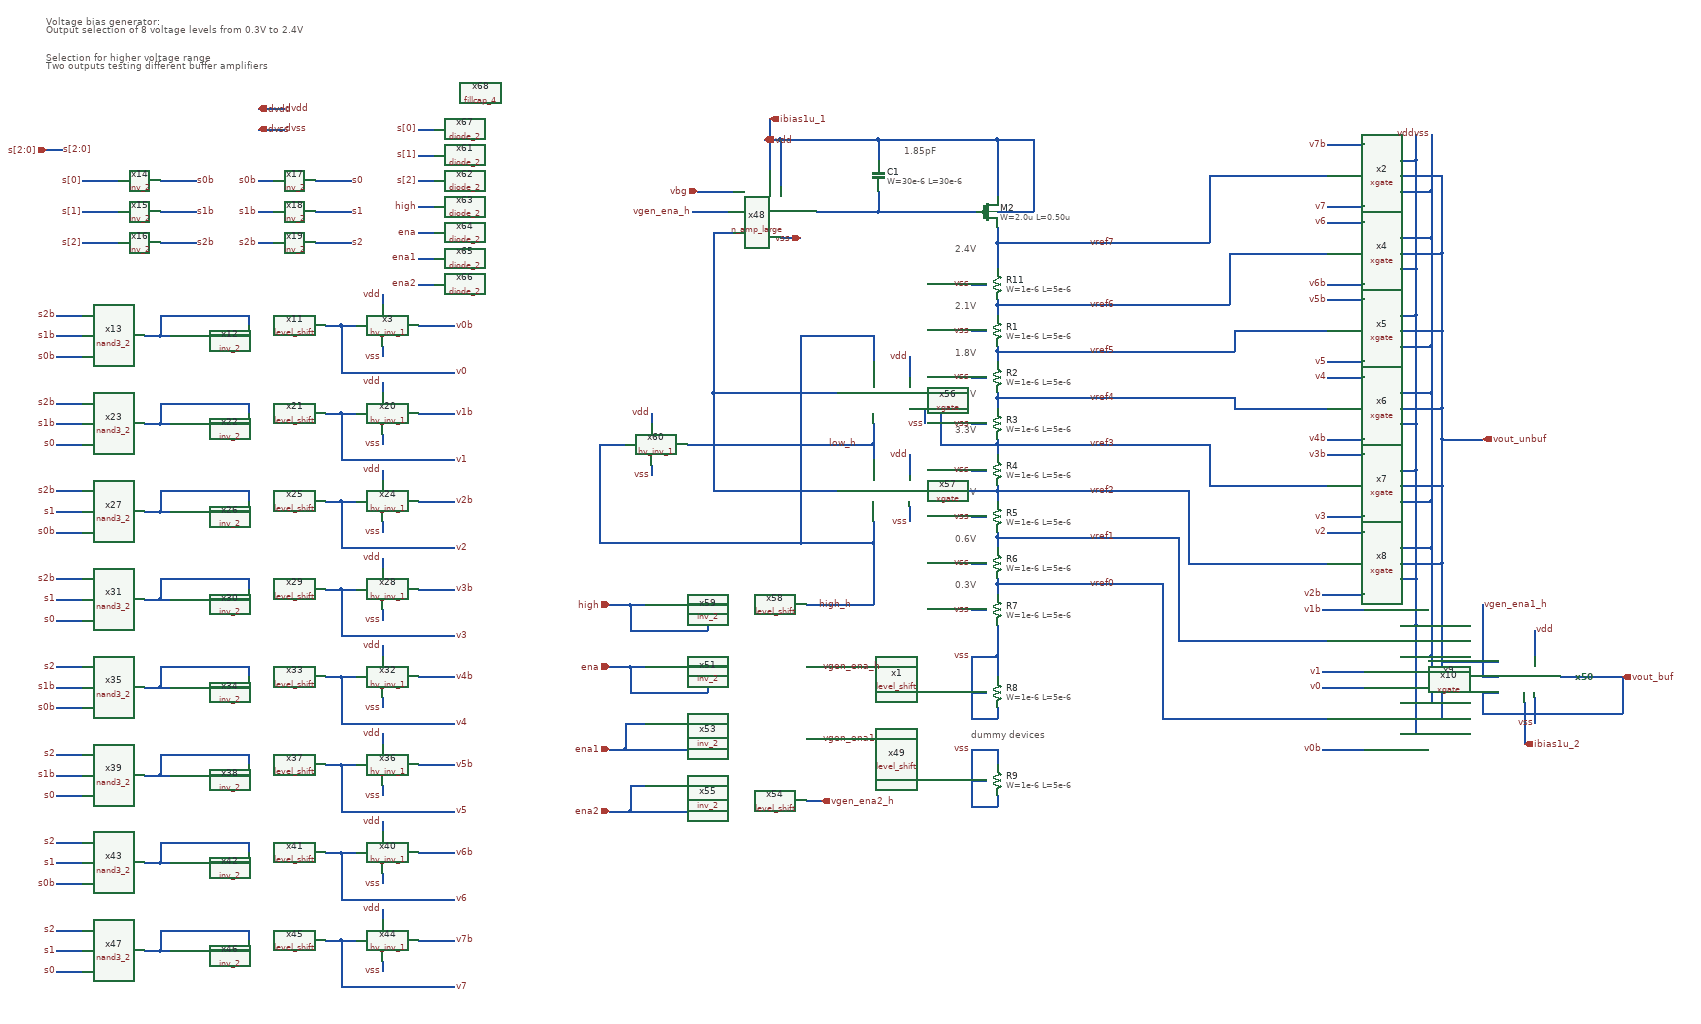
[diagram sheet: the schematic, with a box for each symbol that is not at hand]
v {xschem version=3.4.6 file_version=1.2}
G {}
K {}
V {}
S {}
E {}
T {3.3V} 510 440 0 0 0.4 0.4 {}
T {0.6V} 510 650 0 0 0.4 0.4 {}
T {0.3V} 510 740 0 0 0.4 0.4 {}
T {0.9V} 510 560 0 0 0.4 0.4 {}
T {1.5V} 510 370 0 0 0.4 0.4 {}
T {1.8V} 510 290 0 0 0.4 0.4 {}
T {2.1V} 510 200 0 0 0.4 0.4 {}
T {2.4V} 510 90 0 0 0.4 0.4 {}
T {Voltage bias generator:
Output selection of 8 voltage levels from 0.3V to 2.4V} -1250 -350 0 0 0.4 0.4 {}
T {dummy devices} 540 1030 0 0 0.3 0.3 {}
T {Selection for higher voltage range
Two outputs testing different buffer amplifiers} -1250 -280 0 0 0.4 0.4 {}
T {1.85pF} 410 -100 0 0 0.3 0.3 {}
N 170 80 210 80 {lab=vss}
N 590 -110 590 -0 {lab=vdd}
N 590 30 660 30 {lab=vdd}
N 660 -110 660 30 {lab=vdd}
N 590 -110 660 -110 {lab=vdd}
N 590 830 590 890 {lab=vss}
N 540 890 590 890 {lab=vss}
N 590 750 590 770 {lab=vref0}
N 590 660 590 680 {lab=vref1}
N 590 570 590 590 {lab=vref2}
N 590 480 590 500 {lab=vref3}
N 590 390 590 410 {lab=vref4}
N 590 300 590 320 {lab=vref5}
N 590 210 590 230 {lab=vref6}
N 590 470 590 480 {lab=vref3}
N 10 -10 80 -10 {lab=vbg}
N 590 90 590 140 {lab=vref7}
N 590 750 910 750 {lab=vref0}
N 590 740 590 750 {lab=vref0}
N 910 750 910 1010 {lab=vref0}
N 910 1010 1230 1010 {lab=vref0}
N 590 660 940 660 {lab=vref1}
N 590 650 590 660 {lab=vref1}
N 940 660 940 860 {lab=vref1}
N 940 860 1230 860 {lab=vref1}
N 590 570 960 570 {lab=vref2}
N 590 560 590 570 {lab=vref2}
N 960 570 960 710 {lab=vref2}
N 960 710 1230 710 {lab=vref2}
N 590 480 1000 480 {lab=vref3}
N 1000 480 1000 560 {lab=vref3}
N 1000 560 1230 560 {lab=vref3}
N 590 390 1050 390 {lab=vref4}
N 590 380 590 390 {lab=vref4}
N 1050 390 1050 410 {lab=vref4}
N 1050 410 1230 410 {lab=vref4}
N 590 300 1050 300 {lab=vref5}
N 590 290 590 300 {lab=vref5}
N 1050 260 1050 300 {lab=vref5}
N 1050 260 1230 260 {lab=vref5}
N 590 210 1040 210 {lab=vref6}
N 590 200 590 210 {lab=vref6}
N 1040 110 1040 210 {lab=vref6}
N 1040 110 1230 110 {lab=vref6}
N 590 90 1000 90 {lab=vref7}
N 590 60 590 90 {lab=vref7}
N 1000 -40 1000 90 {lab=vref7}
N 1000 -40 1230 -40 {lab=vref7}
N 1370 -40 1450 -40 {lab=vout_unbuf}
N 1450 900 1450 1010 {lab=vout_unbuf}
N 1370 1010 1450 1010 {lab=vout_unbuf}
N 1370 860 1450 860 {lab=vout_unbuf}
N 1370 710 1450 710 {lab=vout_unbuf}
N 1450 560 1450 710 {lab=vout_unbuf}
N 1370 560 1450 560 {lab=vout_unbuf}
N 1370 410 1450 410 {lab=vout_unbuf}
N 1450 260 1450 410 {lab=vout_unbuf}
N 1370 260 1450 260 {lab=vout_unbuf}
N 1450 110 1450 260 {lab=vout_unbuf}
N 1370 110 1450 110 {lab=vout_unbuf}
N 1450 -40 1450 110 {lab=vout_unbuf}
N 1450 470 1450 560 {lab=vout_unbuf}
N 1370 1040 1400 1040 {lab=vdd}
N 1400 830 1400 1040 {lab=vdd}
N 1370 740 1400 740 {lab=vdd}
N 1400 530 1400 740 {lab=vdd}
N 1370 830 1400 830 {lab=vdd}
N 1400 740 1400 830 {lab=vdd}
N 1370 530 1400 530 {lab=vdd}
N 1400 440 1400 530 {lab=vdd}
N 1370 440 1400 440 {lab=vdd}
N 1400 230 1400 440 {lab=vdd}
N 1370 230 1400 230 {lab=vdd}
N 1400 140 1400 230 {lab=vdd}
N 1370 140 1400 140 {lab=vdd}
N 1400 -70 1400 140 {lab=vdd}
N 1370 -70 1400 -70 {lab=vdd}
N 1400 -120 1400 -70 {lab=vdd}
N 1430 890 1430 980 {lab=vss}
N 1370 980 1430 980 {lab=vss}
N 1370 890 1430 890 {lab=vss}
N 1430 680 1430 890 {lab=vss}
N 1370 680 1430 680 {lab=vss}
N 1430 590 1430 680 {lab=vss}
N 1370 590 1430 590 {lab=vss}
N 1430 380 1430 590 {lab=vss}
N 1370 380 1430 380 {lab=vss}
N 1430 290 1430 380 {lab=vss}
N 1370 290 1430 290 {lab=vss}
N 1430 80 1430 290 {lab=vss}
N 1370 80 1430 80 {lab=vss}
N 1430 -10 1430 80 {lab=vss}
N 1370 -10 1430 -10 {lab=vss}
N 1430 -120 1430 -10 {lab=vss}
N 1220 950 1300 950 {lab=v0}
N 1220 1070 1300 1070 {lab=v0b}
N 1220 920 1300 920 {lab=v1}
N 1220 800 1300 800 {lab=v1b}
N 1220 770 1300 770 {lab=v2b}
N 1230 650 1300 650 {lab=v2}
N 1230 620 1300 620 {lab=v3}
N 1230 500 1300 500 {lab=v3b}
N 1230 470 1300 470 {lab=v4b}
N 1230 350 1300 350 {lab=v4}
N 1230 320 1300 320 {lab=v5}
N 1230 200 1300 200 {lab=v5b}
N 1230 170 1300 170 {lab=v6b}
N 1230 50 1300 50 {lab=v6}
N 1230 20 1300 20 {lab=v7}
N 1230 -100 1300 -100 {lab=v7b}
N -930 270 -860 270 {lab=#net1}
N -1030 270 -1010 270 {lab=#net2}
N -680 250 -650 250 {lab=v0}
N -600 190 -600 210 {lab=vdd}
N -600 290 -600 310 {lab=vss}
N -530 250 -460 250 {lab=v0b}
N -680 250 -680 340 {lab=v0}
N -710 250 -680 250 {lab=v0}
N -680 340 -460 340 {lab=v0}
N -1180 -30 -1110 -30 {lab=s[0]}
N -1180 30 -1110 30 {lab=s[1]}
N -1180 90 -1110 90 {lab=s[2]}
N -1250 -90 -1220 -90 {lab=s[2:0]}
N -1030 -30 -960 -30 {lab=s0b}
N -1030 30 -960 30 {lab=s1b}
N -1030 90 -960 90 {lab=s2b}
N -730 -30 -660 -30 {lab=s0}
N -730 30 -660 30 {lab=s1}
N -730 90 -660 90 {lab=s2}
N -840 -30 -810 -30 {lab=s0b}
N -840 30 -810 30 {lab=s1b}
N -840 90 -810 90 {lab=s2b}
N -1230 230 -1180 230 {lab=s2b}
N -1230 270 -1180 270 {lab=s1b}
N -1230 310 -1180 310 {lab=s0b}
N -1030 230 -1030 270 {lab=#net2}
N -1060 270 -1030 270 {lab=#net2}
N -1030 230 -860 230 {lab=#net2}
N -860 230 -860 250 {lab=#net2}
N -930 440 -860 440 {lab=#net3}
N -1030 440 -1010 440 {lab=#net4}
N -680 420 -650 420 {lab=v1}
N -600 360 -600 380 {lab=vdd}
N -600 460 -600 480 {lab=vss}
N -530 420 -460 420 {lab=v1b}
N -680 420 -680 510 {lab=v1}
N -710 420 -680 420 {lab=v1}
N -680 510 -460 510 {lab=v1}
N -1230 400 -1180 400 {lab=s2b}
N -1230 440 -1180 440 {lab=s1b}
N -1230 480 -1180 480 {lab=s0}
N -1030 400 -1030 440 {lab=#net4}
N -1060 440 -1030 440 {lab=#net4}
N -1030 400 -860 400 {lab=#net4}
N -860 400 -860 420 {lab=#net4}
N -930 610 -860 610 {lab=#net5}
N -1030 610 -1010 610 {lab=#net6}
N -680 590 -650 590 {lab=v2}
N -600 530 -600 550 {lab=vdd}
N -600 630 -600 650 {lab=vss}
N -530 590 -460 590 {lab=v2b}
N -680 590 -680 680 {lab=v2}
N -710 590 -680 590 {lab=v2}
N -680 680 -460 680 {lab=v2}
N -1230 570 -1180 570 {lab=s2b}
N -1230 610 -1180 610 {lab=s1}
N -1230 650 -1180 650 {lab=s0b}
N -1030 570 -1030 610 {lab=#net6}
N -1060 610 -1030 610 {lab=#net6}
N -1030 570 -860 570 {lab=#net6}
N -860 570 -860 590 {lab=#net6}
N -930 780 -860 780 {lab=#net7}
N -1030 780 -1010 780 {lab=#net8}
N -680 760 -650 760 {lab=v3}
N -600 700 -600 720 {lab=vdd}
N -600 800 -600 820 {lab=vss}
N -530 760 -460 760 {lab=v3b}
N -680 760 -680 850 {lab=v3}
N -710 760 -680 760 {lab=v3}
N -680 850 -460 850 {lab=v3}
N -1230 740 -1180 740 {lab=s2b}
N -1230 780 -1180 780 {lab=s1}
N -1230 820 -1180 820 {lab=s0}
N -1030 740 -1030 780 {lab=#net8}
N -1060 780 -1030 780 {lab=#net8}
N -1030 740 -860 740 {lab=#net8}
N -860 740 -860 760 {lab=#net8}
N -930 950 -860 950 {lab=#net9}
N -1030 950 -1010 950 {lab=#net10}
N -680 930 -650 930 {lab=v4}
N -600 870 -600 890 {lab=vdd}
N -600 970 -600 990 {lab=vss}
N -530 930 -460 930 {lab=v4b}
N -680 930 -680 1020 {lab=v4}
N -710 930 -680 930 {lab=v4}
N -680 1020 -460 1020 {lab=v4}
N -1230 910 -1180 910 {lab=s2}
N -1230 950 -1180 950 {lab=s1b}
N -1230 990 -1180 990 {lab=s0b}
N -1030 910 -1030 950 {lab=#net10}
N -1060 950 -1030 950 {lab=#net10}
N -1030 910 -860 910 {lab=#net10}
N -860 910 -860 930 {lab=#net10}
N -930 1120 -860 1120 {lab=#net11}
N -1030 1120 -1010 1120 {lab=#net12}
N -680 1100 -650 1100 {lab=v5}
N -600 1040 -600 1060 {lab=vdd}
N -600 1140 -600 1160 {lab=vss}
N -530 1100 -460 1100 {lab=v5b}
N -680 1100 -680 1190 {lab=v5}
N -710 1100 -680 1100 {lab=v5}
N -680 1190 -460 1190 {lab=v5}
N -1230 1080 -1180 1080 {lab=s2}
N -1230 1120 -1180 1120 {lab=s1b}
N -1230 1160 -1180 1160 {lab=s0}
N -1030 1080 -1030 1120 {lab=#net12}
N -1060 1120 -1030 1120 {lab=#net12}
N -1030 1080 -860 1080 {lab=#net12}
N -860 1080 -860 1100 {lab=#net12}
N -930 1290 -860 1290 {lab=#net13}
N -1030 1290 -1010 1290 {lab=#net14}
N -680 1270 -650 1270 {lab=v6}
N -600 1210 -600 1230 {lab=vdd}
N -600 1310 -600 1330 {lab=vss}
N -530 1270 -460 1270 {lab=v6b}
N -680 1270 -680 1360 {lab=v6}
N -710 1270 -680 1270 {lab=v6}
N -680 1360 -460 1360 {lab=v6}
N -1230 1250 -1180 1250 {lab=s2}
N -1230 1290 -1180 1290 {lab=s1}
N -1230 1330 -1180 1330 {lab=s0b}
N -1030 1250 -1030 1290 {lab=#net14}
N -1060 1290 -1030 1290 {lab=#net14}
N -1030 1250 -860 1250 {lab=#net14}
N -860 1250 -860 1270 {lab=#net14}
N -930 1460 -860 1460 {lab=#net15}
N -1030 1460 -1010 1460 {lab=#net16}
N -680 1440 -650 1440 {lab=v7}
N -600 1380 -600 1400 {lab=vdd}
N -600 1480 -600 1500 {lab=vss}
N -530 1440 -460 1440 {lab=v7b}
N -680 1440 -680 1530 {lab=v7}
N -710 1440 -680 1440 {lab=v7}
N -680 1530 -460 1530 {lab=v7}
N -1230 1420 -1180 1420 {lab=s2}
N -1230 1460 -1180 1460 {lab=s1}
N -1230 1500 -1180 1500 {lab=s0}
N -1030 1420 -1030 1460 {lab=#net16}
N -1060 1460 -1030 1460 {lab=#net16}
N -1030 1420 -860 1420 {lab=#net16}
N -860 1420 -860 1440 {lab=#net16}
N -840 -170 -790 -170 {lab=dvdd}
N -840 -130 -790 -130 {lab=dvss}
N -120 910 -90 910 {lab=ena}
N -120 910 -120 960 {lab=ena}
N -160 910 -120 910 {lab=ena}
N -120 960 30 960 {lab=ena}
N 30 930 30 960 {lab=ena}
N 30 930 70 930 {lab=ena}
N 220 910 250 910 {lab=vgen_ena_h}
N 0 30 70 30 {lab=vgen_ena_h}
N 170 -110 170 -20 {lab=vdd}
N 140 -110 170 -110 {lab=vdd}
N 1450 470 1530 470 {lab=vout_unbuf}
N 1450 410 1450 470 {lab=vout_unbuf}
N 150 -150 150 -50 {lab=ibias1u_1}
N 40 70 80 70 {lab=#net17}
N -10 910 70 910 {lab=#net18}
N 1450 710 1450 860 {lab=vout_unbuf}
N 1450 900 1560 900 {lab=vout_unbuf}
N 1450 860 1450 900 {lab=vout_unbuf}
N 1630 840 1630 890 {lab=vdd}
N 1630 970 1630 1020 {lab=vss}
N 1610 980 1610 1060 {lab=ibias1u_2}
N 1680 930 1800 930 {lab=vout_buf}
N 1800 930 1800 1000 {lab=vout_buf}
N 1530 1000 1800 1000 {lab=vout_buf}
N 1530 960 1530 1000 {lab=vout_buf}
N 1530 960 1560 960 {lab=vout_buf}
N 1530 930 1560 930 {lab=vgen_ena1_h}
N 1530 790 1530 930 {lab=vgen_ena1_h}
N 220 1050 250 1050 {lab=vgen_ena1_h}
N 220 1170 250 1170 {lab=vgen_ena2_h}
N -130 1020 -130 1070 {lab=ena1}
N -160 1070 -130 1070 {lab=ena1}
N 30 1020 30 1050 {lab=#net19}
N 30 1050 70 1050 {lab=#net19}
N -120 1140 -120 1190 {lab=ena2}
N -160 1190 -120 1190 {lab=ena2}
N 40 1140 40 1170 {lab=#net20}
N 40 1170 70 1170 {lab=#net20}
N 420 570 590 570 {lab=vref2}
N 420 380 480 380 {lab=vref3}
N 480 380 480 480 {lab=vref3}
N 480 480 590 480 {lab=vref3}
N 420 310 420 350 {lab=vdd}
N 40 380 280 380 {lab=#net17}
N 40 70 40 380 {lab=#net17}
N 40 570 280 570 {lab=#net17}
N 40 380 40 570 {lab=#net17}
N 350 480 350 510 {lab=low_h}
N 350 630 350 670 {lab=high_h}
N 210 270 210 670 {lab=high_h}
N 210 270 350 270 {lab=high_h}
N 350 270 350 320 {lab=high_h}
N -120 790 -90 790 {lab=high}
N -120 790 -120 840 {lab=high}
N -160 790 -120 790 {lab=high}
N -120 840 30 840 {lab=high}
N 30 810 30 840 {lab=high}
N 30 810 70 810 {lab=high}
N -10 790 70 790 {lab=#net21}
N 210 670 350 670 {lab=high_h}
N 350 670 350 790 {lab=high_h}
N 220 790 350 790 {lab=high_h}
N 350 440 350 480 {lab=low_h}
N 420 500 420 540 {lab=vdd}
N 420 600 420 630 {lab=vss}
N 420 410 450 410 {lab=vss}
N 450 410 450 440 {lab=vss}
N -80 420 -80 440 {lab=vdd}
N -80 520 -80 540 {lab=vss}
N -10 480 350 480 {lab=low_h}
N -180 480 -130 480 {lab=high_h}
N -180 670 210 670 {lab=high_h}
N -180 480 -180 670 {lab=high_h}
N 590 890 590 930 {lab=vss}
N 590 990 590 1010 {lab=vss}
N 540 1010 590 1010 {lab=vss}
N 540 890 540 1010 {lab=vss}
N 590 1070 590 1100 {lab=vss}
N 540 1070 590 1070 {lab=vss}
N 540 1070 540 1180 {lab=vss}
N 540 1180 590 1180 {lab=vss}
N 590 1160 590 1180 {lab=vss}
N -530 -130 -500 -130 {lab=s[0]}
N -530 -80 -500 -80 {lab=s[1]}
N -530 -30 -500 -30 {lab=s[2]}
N -530 20 -500 20 {lab=high}
N -530 70 -500 70 {lab=ena}
N -530 120 -500 120 {lab=ena1}
N -530 170 -500 170 {lab=ena2}
N 460 30 550 30 {lab=#net22}
N 460 -110 590 -110 {lab=vdd}
N 170 -110 260 -110 {lab=vdd}
N 240 30 260 30 {lab=#net22}
N 360 -10 360 30 {lab=#net22}
N 260 30 360 30 {lab=#net22}
N 360 30 460 30 {lab=#net22}
N 360 -110 460 -110 {lab=vdd}
N 360 -110 360 -70 {lab=vdd}
N 260 -110 360 -110 {lab=vdd}
N -130 1070 70 1070 {lab=ena1}
N -120 1190 70 1190 {lab=ena2}
N -120 1140 -90 1140 {lab=ena2}
N -10 1140 40 1140 {lab=#net20}
N -10 1020 30 1020 {lab=#net19}
N -130 1020 -90 1020 {lab=ena1}
N 540 1130 570 1130 {lab=vss}
N 540 960 570 960 {lab=vss}
N 540 800 570 800 {lab=vss}
N 540 710 570 710 {lab=vss}
N 540 620 570 620 {lab=vss}
N 540 530 570 530 {lab=vss}
N 540 440 570 440 {lab=vss}
N 540 350 570 350 {lab=vss}
N 540 260 570 260 {lab=vss}
N 540 170 570 170 {lab=vss}
C {iopin.sym} 140 -110 0 1 {name=p1 lab=vdd}
C {iopin.sym} 210 80 0 0 {name=p2 lab=vss}
C {lab_pin.sym} 540 890 0 0 {name=p3 sig_type=std_logic lab=vss}
C {ipin.sym} 10 -10 0 0 {name=p4 lab=vbg}
C {opin.sym} 1530 470 0 0 {name=p5 lab=vout_unbuf}
C {iopin.sym} 150 -150 0 1 {name=p6 lab=ibias1u_1}
C {xgate.sym} 1310 -50 0 0 {name=x2}
C {hv_inv_1.sym} -590 250 0 0 {name=x3}
C {xgate.sym} 1310 120 2 1 {name=x4}
C {xgate.sym} 1310 250 0 0 {name=x5}
C {xgate.sym} 1310 420 2 1 {name=x6}
C {xgate.sym} 1310 550 0 0 {name=x7}
C {xgate.sym} 1310 720 2 1 {name=x8}
C {xgate.sym} 1310 850 0 0 {name=x9}
C {xgate.sym} 1310 1020 2 1 {name=x10}
C {lab_pin.sym} 1430 -120 1 0 {name=p7 sig_type=std_logic lab=vss}
C {lab_pin.sym} 1400 -120 1 0 {name=p8 sig_type=std_logic lab=vdd}
C {lab_pin.sym} 1230 -100 0 0 {name=p9 sig_type=std_logic lab=v7b}
C {lab_pin.sym} 1230 20 0 0 {name=p10 sig_type=std_logic lab=v7}
C {lab_pin.sym} 1230 170 0 0 {name=p11 sig_type=std_logic lab=v6b}
C {lab_pin.sym} 1230 50 0 0 {name=p12 sig_type=std_logic lab=v6}
C {lab_pin.sym} 1230 320 0 0 {name=p13 sig_type=std_logic lab=v5}
C {lab_pin.sym} 1230 200 0 0 {name=p14 sig_type=std_logic lab=v5b}
C {lab_pin.sym} 1230 350 0 0 {name=p15 sig_type=std_logic lab=v4}
C {lab_pin.sym} 1230 470 0 0 {name=p16 sig_type=std_logic lab=v4b}
C {lab_pin.sym} 1230 500 0 0 {name=p17 sig_type=std_logic lab=v3b}
C {lab_pin.sym} 1230 620 0 0 {name=p18 sig_type=std_logic lab=v3}
C {lab_pin.sym} 1230 650 0 0 {name=p19 sig_type=std_logic lab=v2}
C {lab_pin.sym} 1220 770 0 0 {name=p20 sig_type=std_logic lab=v2b}
C {lab_pin.sym} 1220 800 0 0 {name=p21 sig_type=std_logic lab=v1b}
C {lab_pin.sym} 1220 920 0 0 {name=p22 sig_type=std_logic lab=v1}
C {lab_pin.sym} 1220 950 0 0 {name=p23 sig_type=std_logic lab=v0}
C {lab_pin.sym} 1220 1070 0 0 {name=p24 sig_type=std_logic lab=v0b}
C {level_shift.sym} -710 290 0 0 {name=x11 vdd=vdd vss=vss}
C {inv_2.sym} -970 270 0 0 {name=x12 VDD=dvdd VNW=dvdd VSS=dvss VPW=dvss prefix=gf180mcu_as_sc_mcu7t3v3__ }
C {lab_pin.sym} -600 310 0 0 {name=p25 sig_type=std_logic lab=vss}
C {lab_pin.sym} -600 190 0 0 {name=p26 sig_type=std_logic lab=vdd}
C {lab_pin.sym} -460 340 0 1 {name=p27 sig_type=std_logic lab=v0}
C {lab_pin.sym} -460 250 0 1 {name=p28 sig_type=std_logic lab=v0b}
C {nand3_2.sym} -1120 270 0 0 {name=x13 VDD=dvdd VNW=dvdd VSS=dvss VPW=dvss prefix=gf180mcu_as_sc_mcu7t3v3__ }
C {inv_2.sym} -1070 -30 0 0 {name=x14 VDD=dvdd VNW=dvdd VSS=dvss VPW=dvss prefix=gf180mcu_as_sc_mcu7t3v3__ }
C {inv_2.sym} -1070 30 0 0 {name=x15 VDD=dvdd VNW=dvdd VSS=dvss VPW=dvss prefix=gf180mcu_as_sc_mcu7t3v3__ }
C {inv_2.sym} -1070 90 0 0 {name=x16 VDD=dvdd VNW=dvdd VSS=dvss VPW=dvss prefix=gf180mcu_as_sc_mcu7t3v3__ }
C {lab_pin.sym} -1180 90 0 0 {name=p29 sig_type=std_logic lab=s[2]}
C {lab_pin.sym} -1180 30 0 0 {name=p30 sig_type=std_logic lab=s[1]}
C {lab_pin.sym} -1180 -30 0 0 {name=p31 sig_type=std_logic lab=s[0]}
C {ipin.sym} -1250 -90 0 0 {name=p32 lab=s[2:0]}
C {lab_pin.sym} -1220 -90 0 1 {name=p33 sig_type=std_logic lab=s[2:0]}
C {lab_pin.sym} -960 -30 0 1 {name=p34 sig_type=std_logic lab=s0b}
C {lab_pin.sym} -960 30 0 1 {name=p35 sig_type=std_logic lab=s1b}
C {lab_pin.sym} -960 90 0 1 {name=p36 sig_type=std_logic lab=s2b}
C {inv_2.sym} -770 -30 0 0 {name=x17 VDD=dvdd VNW=dvdd VSS=dvss VPW=dvss prefix=gf180mcu_as_sc_mcu7t3v3__ }
C {inv_2.sym} -770 30 0 0 {name=x18 VDD=dvdd VNW=dvdd VSS=dvss VPW=dvss prefix=gf180mcu_as_sc_mcu7t3v3__ }
C {inv_2.sym} -770 90 0 0 {name=x19 VDD=dvdd VNW=dvdd VSS=dvss VPW=dvss prefix=gf180mcu_as_sc_mcu7t3v3__ }
C {lab_pin.sym} -660 -30 0 1 {name=p37 sig_type=std_logic lab=s0}
C {lab_pin.sym} -660 30 0 1 {name=p38 sig_type=std_logic lab=s1}
C {lab_pin.sym} -660 90 0 1 {name=p39 sig_type=std_logic lab=s2}
C {lab_pin.sym} -840 -30 0 0 {name=p40 sig_type=std_logic lab=s0b}
C {lab_pin.sym} -840 30 0 0 {name=p41 sig_type=std_logic lab=s1b}
C {lab_pin.sym} -840 90 0 0 {name=p42 sig_type=std_logic lab=s2b}
C {lab_pin.sym} -1230 310 0 0 {name=p43 sig_type=std_logic lab=s0b}
C {lab_pin.sym} -1230 270 0 0 {name=p44 sig_type=std_logic lab=s1b}
C {lab_pin.sym} -1230 230 0 0 {name=p45 sig_type=std_logic lab=s2b}
C {hv_inv_1.sym} -590 420 0 0 {name=x20}
C {level_shift.sym} -710 460 0 0 {name=x21 vdd=vdd vss=vss}
C {inv_2.sym} -970 440 0 0 {name=x22 VDD=dvdd VNW=dvdd VSS=dvss VPW=dvss prefix=gf180mcu_as_sc_mcu7t3v3__ }
C {lab_pin.sym} -600 480 0 0 {name=p46 sig_type=std_logic lab=vss}
C {lab_pin.sym} -600 360 0 0 {name=p47 sig_type=std_logic lab=vdd}
C {lab_pin.sym} -460 510 0 1 {name=p48 sig_type=std_logic lab=v1}
C {lab_pin.sym} -460 420 0 1 {name=p49 sig_type=std_logic lab=v1b}
C {nand3_2.sym} -1120 440 0 0 {name=x23 VDD=dvdd VNW=dvdd VSS=dvss VPW=dvss prefix=gf180mcu_as_sc_mcu7t3v3__ }
C {lab_pin.sym} -1230 480 0 0 {name=p50 sig_type=std_logic lab=s0}
C {lab_pin.sym} -1230 440 0 0 {name=p51 sig_type=std_logic lab=s1b}
C {lab_pin.sym} -1230 400 0 0 {name=p52 sig_type=std_logic lab=s2b}
C {hv_inv_1.sym} -590 590 0 0 {name=x24}
C {level_shift.sym} -710 630 0 0 {name=x25 vdd=vdd vss=vss}
C {inv_2.sym} -970 610 0 0 {name=x26 VDD=dvdd VNW=dvdd VSS=dvss VPW=dvss prefix=gf180mcu_as_sc_mcu7t3v3__ }
C {lab_pin.sym} -600 650 0 0 {name=p53 sig_type=std_logic lab=vss}
C {lab_pin.sym} -600 530 0 0 {name=p54 sig_type=std_logic lab=vdd}
C {lab_pin.sym} -460 680 0 1 {name=p55 sig_type=std_logic lab=v2}
C {lab_pin.sym} -460 590 0 1 {name=p56 sig_type=std_logic lab=v2b}
C {nand3_2.sym} -1120 610 0 0 {name=x27 VDD=dvdd VNW=dvdd VSS=dvss VPW=dvss prefix=gf180mcu_as_sc_mcu7t3v3__ }
C {lab_pin.sym} -1230 650 0 0 {name=p57 sig_type=std_logic lab=s0b}
C {lab_pin.sym} -1230 610 0 0 {name=p58 sig_type=std_logic lab=s1}
C {lab_pin.sym} -1230 570 0 0 {name=p59 sig_type=std_logic lab=s2b}
C {hv_inv_1.sym} -590 760 0 0 {name=x28}
C {level_shift.sym} -710 800 0 0 {name=x29 vdd=vdd vss=vss}
C {inv_2.sym} -970 780 0 0 {name=x30 VDD=dvdd VNW=dvdd VSS=dvss VPW=dvss prefix=gf180mcu_as_sc_mcu7t3v3__ }
C {lab_pin.sym} -600 820 0 0 {name=p60 sig_type=std_logic lab=vss}
C {lab_pin.sym} -600 700 0 0 {name=p61 sig_type=std_logic lab=vdd}
C {lab_pin.sym} -460 850 0 1 {name=p62 sig_type=std_logic lab=v3}
C {lab_pin.sym} -460 760 0 1 {name=p63 sig_type=std_logic lab=v3b}
C {nand3_2.sym} -1120 780 0 0 {name=x31 VDD=dvdd VNW=dvdd VSS=dvss VPW=dvss prefix=gf180mcu_as_sc_mcu7t3v3__ }
C {lab_pin.sym} -1230 820 0 0 {name=p64 sig_type=std_logic lab=s0}
C {lab_pin.sym} -1230 780 0 0 {name=p65 sig_type=std_logic lab=s1}
C {lab_pin.sym} -1230 740 0 0 {name=p66 sig_type=std_logic lab=s2b}
C {hv_inv_1.sym} -590 930 0 0 {name=x32}
C {level_shift.sym} -710 970 0 0 {name=x33 vdd=vdd vss=vss}
C {inv_2.sym} -970 950 0 0 {name=x34 VDD=dvdd VNW=dvdd VSS=dvss VPW=dvss prefix=gf180mcu_as_sc_mcu7t3v3__ }
C {lab_pin.sym} -600 990 0 0 {name=p67 sig_type=std_logic lab=vss}
C {lab_pin.sym} -600 870 0 0 {name=p68 sig_type=std_logic lab=vdd}
C {lab_pin.sym} -460 1020 0 1 {name=p69 sig_type=std_logic lab=v4}
C {lab_pin.sym} -460 930 0 1 {name=p70 sig_type=std_logic lab=v4b}
C {nand3_2.sym} -1120 950 0 0 {name=x35 VDD=dvdd VNW=dvdd VSS=dvss VPW=dvss prefix=gf180mcu_as_sc_mcu7t3v3__ }
C {lab_pin.sym} -1230 990 0 0 {name=p71 sig_type=std_logic lab=s0b}
C {lab_pin.sym} -1230 950 0 0 {name=p72 sig_type=std_logic lab=s1b}
C {lab_pin.sym} -1230 910 0 0 {name=p73 sig_type=std_logic lab=s2}
C {hv_inv_1.sym} -590 1100 0 0 {name=x36}
C {level_shift.sym} -710 1140 0 0 {name=x37 vdd=vdd vss=vss}
C {inv_2.sym} -970 1120 0 0 {name=x38 VDD=dvdd VNW=dvdd VSS=dvss VPW=dvss prefix=gf180mcu_as_sc_mcu7t3v3__ }
C {lab_pin.sym} -600 1160 0 0 {name=p74 sig_type=std_logic lab=vss}
C {lab_pin.sym} -600 1040 0 0 {name=p75 sig_type=std_logic lab=vdd}
C {lab_pin.sym} -460 1190 0 1 {name=p76 sig_type=std_logic lab=v5}
C {lab_pin.sym} -460 1100 0 1 {name=p77 sig_type=std_logic lab=v5b}
C {nand3_2.sym} -1120 1120 0 0 {name=x39 VDD=dvdd VNW=dvdd VSS=dvss VPW=dvss prefix=gf180mcu_as_sc_mcu7t3v3__ }
C {lab_pin.sym} -1230 1160 0 0 {name=p78 sig_type=std_logic lab=s0}
C {lab_pin.sym} -1230 1120 0 0 {name=p79 sig_type=std_logic lab=s1b}
C {lab_pin.sym} -1230 1080 0 0 {name=p80 sig_type=std_logic lab=s2}
C {hv_inv_1.sym} -590 1270 0 0 {name=x40}
C {level_shift.sym} -710 1310 0 0 {name=x41 vdd=vdd vss=vss}
C {inv_2.sym} -970 1290 0 0 {name=x42 VDD=dvdd VNW=dvdd VSS=dvss VPW=dvss prefix=gf180mcu_as_sc_mcu7t3v3__ }
C {lab_pin.sym} -600 1330 0 0 {name=p81 sig_type=std_logic lab=vss}
C {lab_pin.sym} -600 1210 0 0 {name=p82 sig_type=std_logic lab=vdd}
C {lab_pin.sym} -460 1360 0 1 {name=p83 sig_type=std_logic lab=v6}
C {lab_pin.sym} -460 1270 0 1 {name=p84 sig_type=std_logic lab=v6b}
C {nand3_2.sym} -1120 1290 0 0 {name=x43 VDD=dvdd VNW=dvdd VSS=dvss VPW=dvss prefix=gf180mcu_as_sc_mcu7t3v3__ }
C {lab_pin.sym} -1230 1330 0 0 {name=p85 sig_type=std_logic lab=s0b}
C {lab_pin.sym} -1230 1290 0 0 {name=p86 sig_type=std_logic lab=s1}
C {lab_pin.sym} -1230 1250 0 0 {name=p87 sig_type=std_logic lab=s2}
C {hv_inv_1.sym} -590 1440 0 0 {name=x44}
C {level_shift.sym} -710 1480 0 0 {name=x45 vdd=vdd vss=vss}
C {inv_2.sym} -970 1460 0 0 {name=x46 VDD=dvdd VNW=dvdd VSS=dvss VPW=dvss prefix=gf180mcu_as_sc_mcu7t3v3__ }
C {lab_pin.sym} -600 1500 0 0 {name=p88 sig_type=std_logic lab=vss}
C {lab_pin.sym} -600 1380 0 0 {name=p89 sig_type=std_logic lab=vdd}
C {lab_pin.sym} -460 1530 0 1 {name=p90 sig_type=std_logic lab=v7}
C {lab_pin.sym} -460 1440 0 1 {name=p91 sig_type=std_logic lab=v7b}
C {nand3_2.sym} -1120 1460 0 0 {name=x47 VDD=dvdd VNW=dvdd VSS=dvss VPW=dvss prefix=gf180mcu_as_sc_mcu7t3v3__ }
C {lab_pin.sym} -1230 1500 0 0 {name=p92 sig_type=std_logic lab=s0}
C {lab_pin.sym} -1230 1460 0 0 {name=p93 sig_type=std_logic lab=s1}
C {lab_pin.sym} -1230 1420 0 0 {name=p94 sig_type=std_logic lab=s2}
C {iopin.sym} -840 -170 0 1 {name=p98 lab=dvdd}
C {iopin.sym} -840 -130 0 1 {name=p99 lab=dvss}
C {lab_pin.sym} -790 -170 0 1 {name=p100 sig_type=std_logic lab=dvdd}
C {lab_pin.sym} -790 -130 0 1 {name=p101 sig_type=std_logic lab=dvss}
C {lab_wire.sym} 820 90 0 0 {name=p102 sig_type=std_logic lab=vref7}
C {lab_wire.sym} 820 210 0 0 {name=p103 sig_type=std_logic lab=vref6}
C {lab_wire.sym} 820 300 0 0 {name=p104 sig_type=std_logic lab=vref5}
C {lab_wire.sym} 820 390 0 0 {name=p105 sig_type=std_logic lab=vref4}
C {lab_wire.sym} 820 480 0 0 {name=p106 sig_type=std_logic lab=vref3}
C {lab_wire.sym} 820 570 0 0 {name=p107 sig_type=std_logic lab=vref2}
C {lab_wire.sym} 820 660 0 0 {name=p108 sig_type=std_logic lab=vref1}
C {lab_wire.sym} 820 750 0 0 {name=p109 sig_type=std_logic lab=vref0}
C {ipin.sym} -160 910 0 0 {name=p112 lab=ena}
C {level_shift.sym} 220 950 0 0 {name=x1 vdd=vdd vss=vss}
C {inv_2.sym} -50 910 0 0 {name=x51 VDD=dvdd VNW=dvdd VSS=dvss VPW=dvss prefix=gf180mcu_as_sc_mcu7t3v3__ }
C {lab_pin.sym} 250 910 0 1 {name=p113 sig_type=std_logic lab=vgen_ena_h}
C {lab_pin.sym} 0 30 0 0 {name=p111 sig_type=std_logic lab=vgen_ena_h}
C {n_amp_large.sym} 230 30 0 0 {name=x48}
C {lab_pin.sym} 250 1050 0 1 {name=p115 sig_type=std_logic lab=vgen_ena1_h}
C {lab_pin.sym} 1630 840 2 0 {name=p116 sig_type=std_logic lab=vdd}
C {lab_pin.sym} 1630 1020 3 0 {name=p117 sig_type=std_logic lab=vss}
C {lab_pin.sym} 1530 790 0 1 {name=p120 sig_type=std_logic lab=vgen_ena1_h}
C {opin.sym} 1800 930 0 0 {name=p119 lab=vout_buf}
C {iopin.sym} 1610 1060 3 1 {name=p118 lab=ibias1u_2}
C {ipin.sym} -160 1070 0 0 {name=p121 lab=ena1}
C {ipin.sym} -160 1190 0 0 {name=p122 lab=ena2}
C {level_shift.sym} 220 1090 0 0 {name=x49 vdd=vdd vss=vss}
C {inv_2.sym} -50 1020 0 0 {name=x53 VDD=dvdd VNW=dvdd VSS=dvss VPW=dvss prefix=gf180mcu_as_sc_mcu7t3v3__ }
C {level_shift.sym} 220 1210 0 0 {name=x54 vdd=vdd vss=vss}
C {inv_2.sym} -50 1140 0 0 {name=x55 VDD=dvdd VNW=dvdd VSS=dvss VPW=dvss prefix=gf180mcu_as_sc_mcu7t3v3__ }
C {xgate.sym} 360 370 0 0 {name=x56}
C {xgate.sym} 360 560 0 0 {name=x57}
C {lab_pin.sym} 420 310 1 0 {name=p124 sig_type=std_logic lab=vdd}
C {lab_pin.sym} 420 500 1 0 {name=p125 sig_type=std_logic lab=vdd}
C {lab_pin.sym} 420 630 3 0 {name=p126 sig_type=std_logic lab=vss}
C {ipin.sym} -160 790 0 0 {name=p127 lab=high}
C {level_shift.sym} 220 830 0 0 {name=x58 vdd=vdd vss=vss}
C {inv_2.sym} -50 790 0 0 {name=x59 VDD=dvdd VNW=dvdd VSS=dvss VPW=dvss prefix=gf180mcu_as_sc_mcu7t3v3__ }
C {lab_wire.sym} 310 790 0 0 {name=p128 sig_type=std_logic lab=high_h}
C {lab_wire.sym} 320 480 0 0 {name=p129 sig_type=std_logic lab=low_h}
C {lab_pin.sym} 450 440 3 0 {name=p130 sig_type=std_logic lab=vss}
C {hv_inv_1.sym} -70 480 0 0 {name=x60}
C {lab_pin.sym} -80 540 0 0 {name=p131 sig_type=std_logic lab=vss}
C {lab_pin.sym} -80 420 0 0 {name=p132 sig_type=std_logic lab=vdd}
C {lab_pin.sym} 540 1070 0 0 {name=p133 sig_type=std_logic lab=vss}
C {diode_2.sym} -410 -130 0 0 {name=x67 VDD=dvdd VNW=dvdd VSS=dvss VPW=dvss prefix=gf180mcu_as_sc_mcu7t3v3__ }
C {lab_pin.sym} -530 -130 0 0 {name=p134 sig_type=std_logic lab=s[0]}
C {lab_pin.sym} -530 -80 0 0 {name=p135 sig_type=std_logic lab=s[1]}
C {lab_pin.sym} -530 -30 0 0 {name=p136 sig_type=std_logic lab=s[2]}
C {lab_pin.sym} -530 20 0 0 {name=p137 sig_type=std_logic lab=high}
C {lab_pin.sym} -530 70 0 0 {name=p138 sig_type=std_logic lab=ena}
C {lab_pin.sym} -530 120 0 0 {name=p139 sig_type=std_logic lab=ena1}
C {lab_pin.sym} -530 170 0 0 {name=p140 sig_type=std_logic lab=ena2}
C {fillcap_4.sym} -410 -200 0 0 {name=x68 VDD=dvdd VNW=dvdd VSS=dvss VPW=dvss prefix=gf180mcu_as_sc_mcu7t3v3__ }
C {diode_2.sym} -410 -80 0 0 {name=x61 VDD=dvdd VNW=dvdd VSS=dvss VPW=dvss prefix=gf180mcu_as_sc_mcu7t3v3__ }
C {diode_2.sym} -410 -30 0 0 {name=x62 VDD=dvdd VNW=dvdd VSS=dvss VPW=dvss prefix=gf180mcu_as_sc_mcu7t3v3__ }
C {diode_2.sym} -410 20 0 0 {name=x63 VDD=dvdd VNW=dvdd VSS=dvss VPW=dvss prefix=gf180mcu_as_sc_mcu7t3v3__ }
C {diode_2.sym} -410 70 0 0 {name=x64 VDD=dvdd VNW=dvdd VSS=dvss VPW=dvss prefix=gf180mcu_as_sc_mcu7t3v3__ }
C {diode_2.sym} -410 120 0 0 {name=x65 VDD=dvdd VNW=dvdd VSS=dvss VPW=dvss prefix=gf180mcu_as_sc_mcu7t3v3__ }
C {diode_2.sym} -410 170 0 0 {name=x66 VDD=dvdd VNW=dvdd VSS=dvss VPW=dvss prefix=gf180mcu_as_sc_mcu7t3v3__ }
C {gf180mcu_fd_pr/cap_mim_2f0fF.sym} 360 -40 0 0 {name=C1
W=30e-6
L=30e-6
model=cap_mim_2f0_m4m5_noshield
spiceprefix=X
m=1}
C {opin.sym} 250 1170 0 0 {name=p95 lab=vgen_ena2_h}
C {gf180mcu_fd_pr/ppolyf_u_1k.sym} 590 170 0 0 {name=R11
W=1e-6
L=5e-6
model=ppolyf_u_1k
spiceprefix=X
m=1}
C {gf180mcu_fd_pr/ppolyf_u_1k.sym} 590 260 0 0 {name=R1
W=1e-6
L=5e-6
model=ppolyf_u_1k
spiceprefix=X
m=1}
C {gf180mcu_fd_pr/ppolyf_u_1k.sym} 590 350 0 0 {name=R2
W=1e-6
L=5e-6
model=ppolyf_u_1k
spiceprefix=X
m=1}
C {gf180mcu_fd_pr/ppolyf_u_1k.sym} 590 440 0 0 {name=R3
W=1e-6
L=5e-6
model=ppolyf_u_1k
spiceprefix=X
m=1}
C {gf180mcu_fd_pr/ppolyf_u_1k.sym} 590 530 0 0 {name=R4
W=1e-6
L=5e-6
model=ppolyf_u_1k
spiceprefix=X
m=1}
C {gf180mcu_fd_pr/ppolyf_u_1k.sym} 590 620 0 0 {name=R5
W=1e-6
L=5e-6
model=ppolyf_u_1k
spiceprefix=X
m=1}
C {gf180mcu_fd_pr/ppolyf_u_1k.sym} 590 710 0 0 {name=R6
W=1e-6
L=5e-6
model=ppolyf_u_1k
spiceprefix=X
m=1}
C {gf180mcu_fd_pr/ppolyf_u_1k.sym} 590 800 0 0 {name=R7
W=1e-6
L=5e-6
model=ppolyf_u_1k
spiceprefix=X
m=1}
C {gf180mcu_fd_pr/ppolyf_u_1k.sym} 590 960 0 0 {name=R8
W=1e-6
L=5e-6
model=ppolyf_u_1k
spiceprefix=X
m=1}
C {gf180mcu_fd_pr/ppolyf_u_1k.sym} 590 1130 0 0 {name=R9
W=1e-6
L=5e-6
model=ppolyf_u_1k
spiceprefix=X
m=1}
C {lab_pin.sym} 540 800 0 0 {name=p96 sig_type=std_logic lab=vss}
C {lab_pin.sym} 540 710 0 0 {name=p97 sig_type=std_logic lab=vss}
C {lab_pin.sym} 540 620 0 0 {name=p110 sig_type=std_logic lab=vss}
C {lab_pin.sym} 540 530 0 0 {name=p114 sig_type=std_logic lab=vss}
C {lab_pin.sym} 540 440 0 0 {name=p123 sig_type=std_logic lab=vss}
C {lab_pin.sym} 540 350 0 0 {name=p141 sig_type=std_logic lab=vss}
C {lab_pin.sym} 540 260 0 0 {name=p142 sig_type=std_logic lab=vss}
C {lab_pin.sym} 540 170 0 0 {name=p143 sig_type=std_logic lab=vss}
C {gf180mcu_fd_pr/pfet_05v0.sym} 570 30 0 0 {name=M2
L=0.50u
W=2.0u
nf=1
m=1
ad="'int((nf+1)/2) * W/nf * 0.18u'"
pd="'2*int((nf+1)/2) * (W/nf + 0.18u)'"
as="'int((nf+2)/2) * W/nf * 0.18u'"
ps="'2*int((nf+2)/2) * (W/nf + 0.18u)'"
nrd="'0.18u / W'" nrs="'0.18u / W'"
sa=0 sb=0 sd=0
model=pfet_05v0
spiceprefix=X
}
C {se_folded_cascode_p_5v.sym} 1710 930 0 0 {name=x50}
